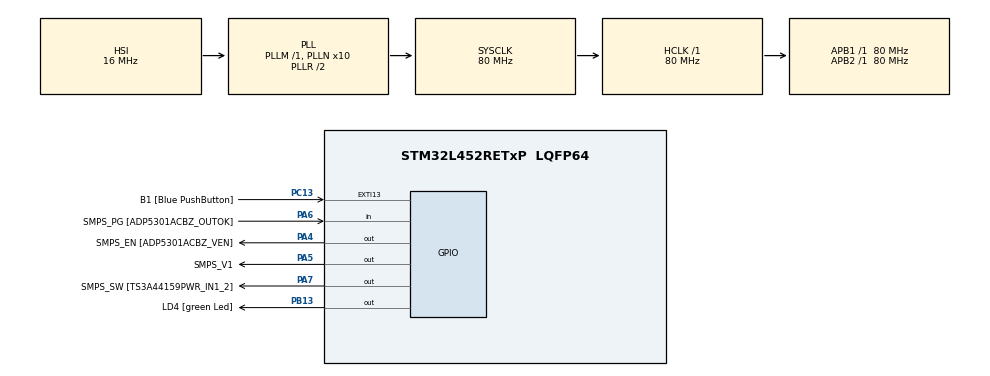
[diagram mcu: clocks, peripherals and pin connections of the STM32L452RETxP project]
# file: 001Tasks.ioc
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Mcu.Family=STM32L4
PA2.GPIO_PuPd=GPIO_NOPULL
VP_SYS_VS_tim6.Mode=TIM6
RCC.CortexFreq_Value=80000000
NVIC.TIM6_DAC_IRQn=true\:0\:0\:false\:false\:true\:false\:true
PH0-OSC_IN\ (PH0).Signal=RCC_OSC_IN
PA3.GPIO_PuPd=GPIO_NOPULL
PA2.GPIO_Speed=GPIO_SPEED_FREQ_VERY_HIGH
PA6.GPIO_Label=SMPS_PG [ADP5301ACBZ_OUTOK]
PC13.GPIO_Label=B1 [Blue PushButton]
PB13.GPIO_Label=LD4 [green Led]
PA3.GPIO_Speed=GPIO_SPEED_FREQ_VERY_HIGH
PB13.Signal=GPIO_Output
RCC.SYSCLKSource=RCC_SYSCLKSOURCE_PLLCLK
ProjectManager.StackSize=0x400
PA14\ (JTCK/SWCLK).Signal=SYS_JTCK-SWCLK
RCC.HCLKFreq_Value=80000000
RCC.APB2TimFreq_Value=80000000
RCC.AHBFreq_Value=80000000
RCC.PREFETCH_ENABLE=1
RCC.HSE_VALUE=8000000
PA13\ (JTMS/SWDIO).GPIO_Label=TMS
PA6.GPIO_PuPd=GPIO_PULLUP
PA5.GPIO_PuPd=GPIO_NOPULL
PC13.GPIO_PuPd=GPIO_NOPULL
Mcu.Package=LQFP64
PA6.Signal=GPIO_Input
NVIC.TimeBase=TIM6_DAC_IRQn
PA2.GPIO_Label=USART_TX
NVIC.TimeBaseIP=TIM6
PA14\ (JTCK/SWCLK).GPIO_Label=TCK
RCC.APB1TimFreq_Value=80000000
PA4.GPIO_Label=SMPS_EN [ADP5301ACBZ_VEN]
RCC.HSI48_VALUE=48000000
PA3.Signal=USART2_RX
PA2.GPIO_Mode=GPIO_MODE_AF_PP
PB3\ (JTDO/TRACESWO).GPIO_Label=SWO
RCC.MSI_VALUE=4000000
RCC.PLLSourceVirtual=RCC_PLLSOURCE_HSI
PC13.Signal=GPXTI13
PC15-OSC32_OUT\ (PC15).Signal=RCC_OSC32_OUT
PH1-OSC_OUT\ (PH1).Signal=RCC_OSC_OUT
PB3\ (JTDO/TRACESWO).Signal=SYS_JTDO-SWO
ProjectManager.TargetToolchain=STM32CubeIDE
PA3.GPIO_Mode=GPIO_MODE_AF_PP
RCC.USBFreq_Value=64000000
RCC.LSE_VALUE=32768
PA5.Signal=GPIO_Output
board=NUCLEO-L452RE-P
RCC.VCOOutputFreq_Value=160000000
RCC.APB2Freq_Value=80000000
PA5.GPIO_ModeDefaultOutputPP=GPIO_MODE_OUTPUT_PP
RCC.ADCFreq_Value=64000000
Mcu.Name=STM32L452RETxP
PA2.Signal=USART2_TX
PA4.Signal=GPIO_Output
RCC.SYSCLKFreq_VALUE=80000000
PA7.GPIO_Label=SMPS_SW [TS3A44159PWR_IN1_2]
PA5.GPIO_Label=SMPS_V1
PC13.GPIO_ModeDefaultEXTI=GPIO_MODE_IT_FALLING
PC14-OSC32_IN\ (PC14).Signal=RCC_OSC32_IN
ProjectManager.HeapSize=0x200
RCC.HSI_VALUE=16000000
PA5.GPIO_Speed=GPIO_SPEED_FREQ_LOW
NVIC.PriorityGroup=NVIC_PRIORITYGROUP_4
PH0-OSC_IN\ (PH0).GPIO_Label=MCO
RCC.PLLN=10
RCC.APB1Freq_Value=80000000
PA13\ (JTMS/SWDIO).Signal=SYS_JTMS-SWDIO
PA3.GPIO_Label=USART_RX
PA7.Signal=GPIO_Output

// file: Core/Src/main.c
/* USER CODE BEGIN Header */
/**
  ******************************************************************************
  * @file           : main.c
  * @brief          : Main program body
  ******************************************************************************
  * @attention
  *
  * <h2><center>&copy; Copyright (c) 2022 STMicroelectronics.
  * All rights reserved.</center></h2>
  *
  * This software component is licensed by ST under BSD 3-Clause license,
  * the "License"; You may not use this file except in compliance with the
  * License. You may obtain a copy of the License at:
  *                        opensource.org/licenses/BSD-3-Clause
  *
  ******************************************************************************
  */
/* USER CODE END Header */
#include "main.h"

/* USER CODE BEGIN Includes */
#include <stdio.h>
#include "FreeRTOS.h"
#include "task.h"
/* USER CODE END Includes */

void SystemClock_Config(void);
static void MX_GPIO_Init(void);
/* USER CODE BEGIN PFP */
static void ledr_handler(void *parameters);
static void ledy_handler(void *parameters);
static void ledg_handler(void *parameters);
/* USER CODE END PFP */

int main(void)
{

  /* MCU Configuration--------------------------------------------------------*/

  /* Reset of all peripherals, Initializes the Flash interface and the Systick. */
  HAL_Init();

  /* Configure the system clock */
  SystemClock_Config();

  /* Initialize all configured peripherals */
  MX_GPIO_Init();
  /* USER CODE BEGIN 2 */
  TaskHandle_t task1_handle;
  TaskHandle_t task2_handle;
  TaskHandle_t task3_handle;
  BaseType_t status;

  status = xTaskCreate(ledr_handler, "LEDR", 200, NULL, 2, &task1_handle);
  configASSERT(status == pdPASS);

  status = xTaskCreate(ledy_handler, "LEDY", 200, NULL, 2, &task2_handle);
  configASSERT(status == pdPASS);

  status = xTaskCreate(ledg_handler, "LEDG", 200, NULL, 2, &task3_handle);
  configASSERT(status == pdPASS);

  // Start scheduler
  vTaskStartScheduler();

  /* USER CODE END 2 */

  /* Infinite loop */
  while (1)
  {

  }
}

void SystemClock_Config(void)
{
  RCC_OscInitTypeDef RCC_OscInitStruct = {0};
  RCC_ClkInitTypeDef RCC_ClkInitStruct = {0};

  /** Initializes the RCC Oscillators according to the specified parameters
  * in the RCC_OscInitTypeDef structure.
  */
  RCC_OscInitStruct.OscillatorType = RCC_OSCILLATORTYPE_HSI;
  RCC_OscInitStruct.HSIState = RCC_HSI_ON;
  RCC_OscInitStruct.HSICalibrationValue = RCC_HSICALIBRATION_DEFAULT;
  RCC_OscInitStruct.PLL.PLLState = RCC_PLL_ON;
  RCC_OscInitStruct.PLL.PLLSource = RCC_PLLSOURCE_HSI;
  RCC_OscInitStruct.PLL.PLLM = 1;
  RCC_OscInitStruct.PLL.PLLN = 10;
  RCC_OscInitStruct.PLL.PLLP = RCC_PLLP_DIV7;
  RCC_OscInitStruct.PLL.PLLQ = RCC_PLLQ_DIV2;
  RCC_OscInitStruct.PLL.PLLR = RCC_PLLR_DIV2;
  if (HAL_RCC_OscConfig(&RCC_OscInitStruct) != HAL_OK)
  {
    Error_Handler();
  }
  /** Initializes the CPU, AHB and APB buses clocks
  */
  RCC_ClkInitStruct.ClockType = RCC_CLOCKTYPE_HCLK|RCC_CLOCKTYPE_SYSCLK
                              |RCC_CLOCKTYPE_PCLK1|RCC_CLOCKTYPE_PCLK2;
  RCC_ClkInitStruct.SYSCLKSource = RCC_SYSCLKSOURCE_PLLCLK;
  RCC_ClkInitStruct.AHBCLKDivider = RCC_SYSCLK_DIV1;
  RCC_ClkInitStruct.APB1CLKDivider = RCC_HCLK_DIV1;
  RCC_ClkInitStruct.APB2CLKDivider = RCC_HCLK_DIV1;

  if (HAL_RCC_ClockConfig(&RCC_ClkInitStruct, FLASH_LATENCY_4) != HAL_OK)
  {
    Error_Handler();
  }
  /** Configure the main internal regulator output voltage
  */
  if (HAL_PWREx_ControlVoltageScaling(PWR_REGULATOR_VOLTAGE_SCALE1) != HAL_OK)
  {
    Error_Handler();
  }
}

static void MX_GPIO_Init(void)
{
  GPIO_InitTypeDef GPIO_InitStruct = {0};

  /* GPIO Ports Clock Enable */
  __HAL_RCC_GPIOC_CLK_ENABLE();
  __HAL_RCC_GPIOH_CLK_ENABLE();
  __HAL_RCC_GPIOA_CLK_ENABLE();
  __HAL_RCC_GPIOB_CLK_ENABLE();

  /*Configure GPIO pin Output Level */
  HAL_GPIO_WritePin(GPIOC, LEDR_Pin|LEDY_Pin|LEDG_Pin, GPIO_PIN_RESET);

  /*Configure GPIO pin Output Level */
  HAL_GPIO_WritePin(GPIOA, SMPS_EN_Pin|SMPS_V1_Pin|SMPS_SW_Pin, GPIO_PIN_RESET);

  /*Configure GPIO pin Output Level */
  HAL_GPIO_WritePin(LD4_GPIO_Port, LD4_Pin, GPIO_PIN_RESET);

  /*Configure GPIO pin : B1_Pin */
  GPIO_InitStruct.Pin = B1_Pin;
  GPIO_InitStruct.Mode = GPIO_MODE_IT_FALLING;
  GPIO_InitStruct.Pull = GPIO_NOPULL;
  HAL_GPIO_Init(B1_GPIO_Port, &GPIO_InitStruct);

  /*Configure GPIO pins : LEDR_Pin LEDY_Pin LEDG_Pin */
  GPIO_InitStruct.Pin = LEDR_Pin|LEDY_Pin|LEDG_Pin;
  GPIO_InitStruct.Mode = GPIO_MODE_OUTPUT_PP;
  GPIO_InitStruct.Pull = GPIO_NOPULL;
  GPIO_InitStruct.Speed = GPIO_SPEED_FREQ_LOW;
  HAL_GPIO_Init(GPIOC, &GPIO_InitStruct);

  /*Configure GPIO pins : USART_TX_Pin USART_RX_Pin */
  GPIO_InitStruct.Pin = USART_TX_Pin|USART_RX_Pin;
  GPIO_InitStruct.Mode = GPIO_MODE_AF_PP;
  GPIO_InitStruct.Pull = GPIO_NOPULL;
  GPIO_InitStruct.Speed = GPIO_SPEED_FREQ_VERY_HIGH;
  GPIO_InitStruct.Alternate = GPIO_AF7_USART2;
  HAL_GPIO_Init(GPIOA, &GPIO_InitStruct);

  /*Configure GPIO pins : SMPS_EN_Pin SMPS_V1_Pin SMPS_SW_Pin */
  GPIO_InitStruct.Pin = SMPS_EN_Pin|SMPS_V1_Pin|SMPS_SW_Pin;
  GPIO_InitStruct.Mode = GPIO_MODE_OUTPUT_PP;
  GPIO_InitStruct.Pull = GPIO_NOPULL;
  GPIO_InitStruct.Speed = GPIO_SPEED_FREQ_LOW;
  HAL_GPIO_Init(GPIOA, &GPIO_InitStruct);

  /*Configure GPIO pin : SMPS_PG_Pin */
  GPIO_InitStruct.Pin = SMPS_PG_Pin;
  GPIO_InitStruct.Mode = GPIO_MODE_INPUT;
  GPIO_InitStruct.Pull = GPIO_PULLUP;
  HAL_GPIO_Init(SMPS_PG_GPIO_Port, &GPIO_InitStruct);

  /*Configure GPIO pin : LD4_Pin */
  GPIO_InitStruct.Pin = LD4_Pin;
  GPIO_InitStruct.Mode = GPIO_MODE_OUTPUT_PP;
  GPIO_InitStruct.Pull = GPIO_NOPULL;
  GPIO_InitStruct.Speed = GPIO_SPEED_FREQ_LOW;
  HAL_GPIO_Init(LD4_GPIO_Port, &GPIO_InitStruct);

}

/* USER CODE BEGIN 4 */
static void ledg_handler(void *parameters)
{
    while(1)
    {
        HAL_GPIO_TogglePin(LEDG_GPIO_Port, LEDG_Pin);
        HAL_Delay(1000);
    }
}

static void ledy_handler(void *parameters)
{
    while(1)
    {
        HAL_GPIO_TogglePin(LEDY_GPIO_Port, LEDY_Pin);
        HAL_Delay(800);
    }
}

static void ledr_handler(void *parameters)
{
    while(1)
    {
        HAL_GPIO_TogglePin(LEDR_GPIO_Port, LEDR_Pin);
        HAL_Delay(400);
    }
}
/* USER CODE END 4 */

 /**
  * @brief  Period elapsed callback in non blocking mode
  * @note   This function is called  when TIM6 interrupt took place, inside
  * HAL_TIM_IRQHandler(). It makes a direct call to HAL_IncTick() to increment
  * a global variable "uwTick" used as application time base.
  * @param  htim : TIM handle
  * @retval None
  */
void HAL_TIM_PeriodElapsedCallback(TIM_HandleTypeDef *htim)
{
  if (htim->Instance == TIM6) {
    HAL_IncTick();
  }
}

void Error_Handler(void)
{
  __disable_irq();
  while (1)
  {
  }
}

/************************ (C) COPYRIGHT STMicroelectronics *****END OF FILE****/
